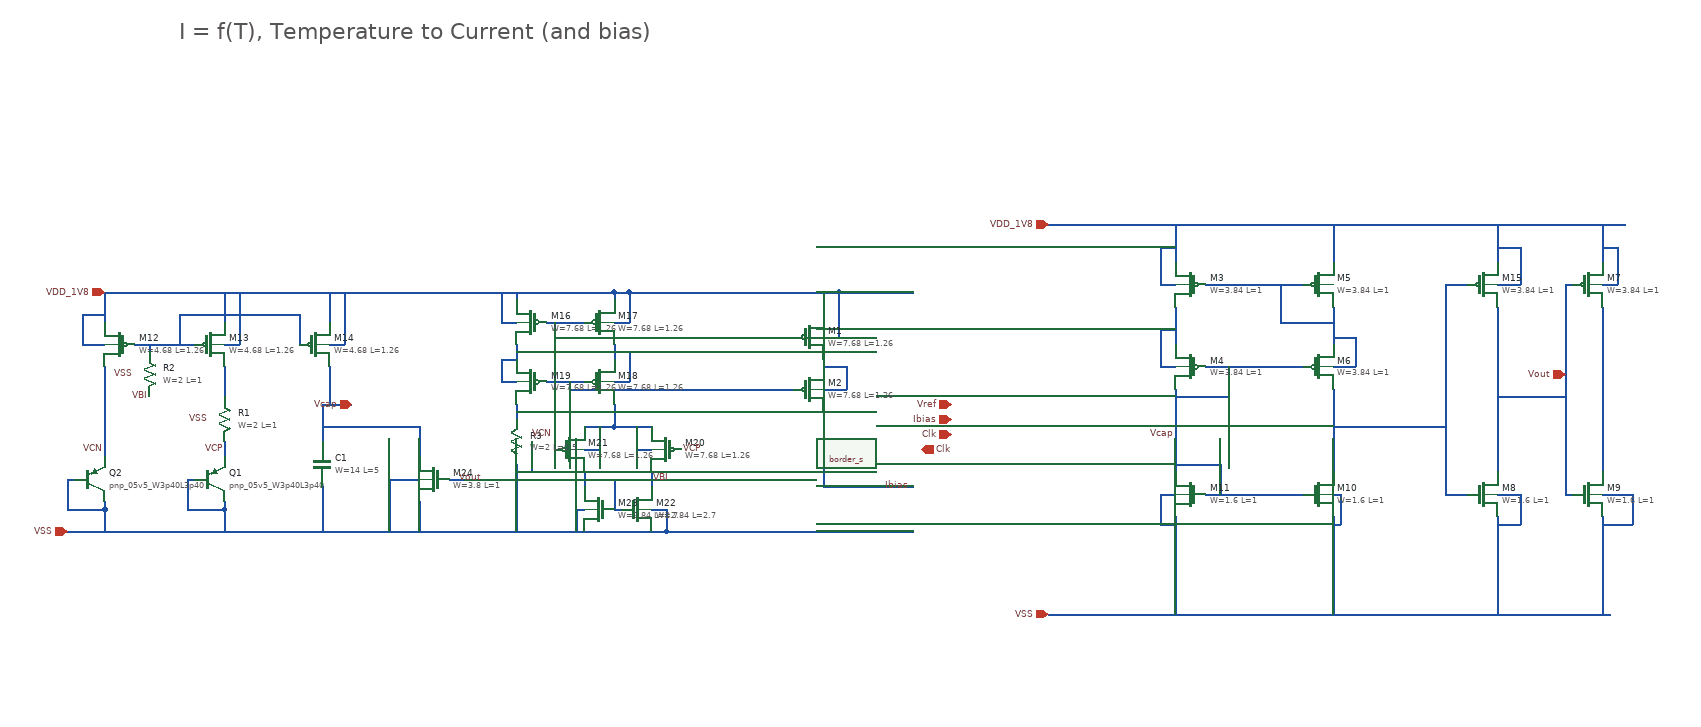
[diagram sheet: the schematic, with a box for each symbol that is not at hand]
v {xschem version=3.4.4 file_version=1.2
}
G {}
K {}
V {}
S {}
E {}
T {I = f(T), Temperature to Current (and bias)} -560 -540 0 0 1 1 {}
N -660 -180 -660 -140 {
lab=VDD_1V8}
N -500 -180 -500 -140 {
lab=VDD_1V8}
N -500 -80 -500 -40 {
lab=#net1}
N -500 20 -500 40 {
lab=VCP}
N -550 70 -540 70 {
lab=VSS}
N -550 70 -550 110 {
lab=VSS}
N -550 110 -500 110 {
lab=VSS}
N -500 100 -500 110 {
lab=VSS}
N -710 70 -700 70 {
lab=VSS}
N -710 70 -710 110 {
lab=VSS}
N -710 110 -660 110 {
lab=VSS}
N -660 100 -660 110 {
lab=VSS}
N -660 -80 -660 40 {
lab=VCN}
N -660 -180 20 -180 {
lab=VDD_1V8}
N -620 -110 -540 -110 {
lab=#net2}
N -560 -150 -560 -110 {
lab=#net2}
N -360 -180 -360 -140 {
lab=VDD_1V8}
N -560 -150 -400 -150 {
lab=#net2}
N -400 -150 -400 -110 {
lab=#net2}
N -360 -80 -360 -30 {
lab=Vcap}
N -110 -180 -110 -170 {
lab=VDD_1V8}
N 20 -180 20 -170 {
lab=VDD_1V8}
N -70 -140 -20 -140 {
lab=#net3}
N -60 -140 -60 -110 {
lab=#net3}
N -70 -60 -20 -60 {
lab=#net4}
N -60 -60 -60 -20 {
lab=#net4}
N -110 -20 -60 -20 {
lab=#net4}
N -110 -110 -110 -90 {
lab=#net3}
N -110 -100 -60 -100 {
lab=#net3}
N -60 -110 -60 -100 {
lab=#net3}
N -110 -30 -110 -10 {
lab=#net4}
N 20 -110 20 -90 {
lab=#net5}
N 20 -30 20 0 {
lab=#net6}
N -20 0 20 0 {
lab=#net6}
N 20 0 70 0 {
lab=#net6}
N -20 60 -20 80 {
lab=#net7}
N 70 60 70 80 {
lab=VBI}
N 20 110 30 110 {
lab=VBI}
N 20 70 20 110 {
lab=VBI}
N 20 70 70 70 {
lab=VBI}
N -20 140 70 140 {
lab=VSS}
N -710 140 -20 140 {
lab=VSS}
N -660 110 -660 140 {
lab=VSS}
N -500 110 -500 140 {
lab=VSS}
N -110 50 -110 140 {
lab=VSS}
N -90 20 -90 60 {
lab=VSS}
N -110 60 -90 60 {
lab=VSS}
N -60 10 -60 30 {
lab=VCN}
N 70 110 90 110 {
lab=VSS}
N 90 110 90 140 {
lab=VSS}
N 70 140 90 140 {
lab=VSS}
N -30 110 -20 110 {
lab=VSS}
N -30 110 -30 140 {
lab=VSS}
N 20 -60 40 -60 {
lab=#net5}
N 40 -100 40 -60 {
lab=#net5}
N 20 -100 40 -100 {
lab=#net5}
N 20 -140 40 -140 {
lab=VDD_1V8}
N 40 -180 40 -140 {
lab=VDD_1V8}
N 20 -180 40 -180 {
lab=VDD_1V8}
N -130 -60 -110 -60 {
lab=#net3}
N -130 -90 -130 -60 {
lab=#net3}
N -130 -90 -110 -90 {
lab=#net3}
N -130 -140 -110 -140 {
lab=VDD_1V8}
N -130 -180 -130 -140 {
lab=VDD_1V8}
N -20 30 0 30 {
lab=#net6}
N 0 0 0 30 {
lab=#net6}
N 50 30 70 30 {
lab=#net6}
N 50 0 50 30 {
lab=#net6}
N -360 -110 -340 -110 {
lab=VDD_1V8}
N -340 -180 -340 -110 {
lab=VDD_1V8}
N -500 -110 -480 -110 {
lab=VDD_1V8}
N -480 -180 -480 -110 {
lab=VDD_1V8}
N -690 -110 -660 -110 {
lab=VDD_1V8}
N -690 -150 -690 -110 {
lab=VDD_1V8}
N -690 -150 -660 -150 {
lab=VDD_1V8}
N -370 -30 -370 20 {
lab=Vcap}
N -370 80 -370 130 {
lab=VSS}
N -200 70 -180 70 {
lab=Vcap}
N -280 70 -240 70 {
lab=VSS}
N -240 0 -240 40 {
lab=Vcap}
N -370 -30 -330 -30 {
lab=Vcap}
N -280 70 -280 130 {
lab=VSS}
N -240 100 -240 130 {
lab=VSS}
N -280 130 -280 140 {
lab=VSS}
N -240 130 -240 140 {
lab=VSS}
N -370 130 -370 140 {
lab=VSS}
N -600 -110 -600 -100 {
lab=#net2}
N -370 0 -240 0 {
lab=Vcap}
N 40 -180 170 -180 {
lab=VDD_1V8}
N 90 140 220 140 {
lab=VSS}
N -60 -120 260 -120 {
lab=#net3}
N -40 -60 -40 -50 {
lab=#net4}
N -40 -50 260 -50 {
lab=#net4}
N 300 -90 300 -80 {
lab=#net8}
N 300 -50 330 -50 {
lab=#net8}
N 330 -80 330 -50 {
lab=#net8}
N 300 -80 330 -80 {
lab=#net8}
N 300 -120 320 -120 {
lab=VDD_1V8}
N 320 -180 320 -120 {
lab=VDD_1V8}
N 170 -180 320 -180 {
lab=VDD_1V8}
N 300 -180 300 -150 {
lab=VDD_1V8}
N 300 -20 300 40 {
lab=Ibias}
N 320 -180 420 -180 {
lab=VDD_1V8}
N 220 140 420 140 {
lab=VSS}
N 300 40 300 80 {
lab=Ibias}
N 300 80 420 80 {
lab=Ibias}
N 600 -270 1350 -270 {
lab=VDD_1V8}
N 600 250 1350 250 {
lab=VSS}
N 980 120 980 250 {
lab=VSS}
N 1350 -270 1370 -270 {
lab=VDD_1V8}
N 750 90 770 90 {
lab=VSS}
N 750 90 750 130 {
lab=VSS}
N 750 130 770 130 {
lab=VSS}
N 980 90 990 90 {
lab=VSS}
N 990 90 990 130 {
lab=VSS}
N 980 130 990 130 {
lab=VSS}
N 750 -190 770 -190 {
lab=VDD_1V8}
N 750 -240 750 -190 {
lab=VDD_1V8}
N 750 -240 770 -240 {
lab=VDD_1V8}
N 750 -80 770 -80 {
lab=#net9}
N 750 -130 750 -80 {
lab=#net9}
N 750 -130 770 -130 {
lab=#net9}
N 770 -270 770 -220 {
lab=VDD_1V8}
N 770 -160 770 -110 {
lab=#net9}
N 980 -160 980 -110 {
lab=#net10}
N 980 -270 980 -220 {
lab=VDD_1V8}
N 810 -190 940 -190 {
lab=#net10}
N 910 -190 910 -140 {
lab=#net10}
N 910 -140 980 -140 {
lab=#net10}
N 810 -80 940 -80 {
lab=Vcap}
N 980 -50 980 60 {
lab=#net11}
N 770 -50 770 60 {
lab=Vcap}
N 770 120 770 250 {
lab=VSS}
N 810 90 940 90 {
lab=Vcap}
N 830 50 830 90 {
lab=Vcap}
N 770 50 830 50 {
lab=Vcap}
N 840 -80 840 -40 {
lab=Vcap}
N 770 -40 840 -40 {
lab=Vcap}
N 980 -80 1010 -80 {
lab=#net10}
N 1010 -120 1010 -80 {
lab=#net10}
N 980 -120 1010 -120 {
lab=#net10}
N 1200 -270 1200 -220 {
lab=VDD_1V8}
N 1340 -270 1340 -220 {
lab=VDD_1V8}
N 1200 -160 1200 60 {
lab=Vout}
N 1340 -160 1340 60 {
lab=#net12}
N 1200 -190 1230 -190 {
lab=VDD_1V8}
N 1230 -240 1230 -190 {
lab=VDD_1V8}
N 1200 -240 1230 -240 {
lab=VDD_1V8}
N 1340 -190 1360 -190 {
lab=VDD_1V8}
N 1360 -240 1360 -190 {
lab=VDD_1V8}
N 1340 -240 1360 -240 {
lab=VDD_1V8}
N 1290 -190 1300 -190 {
lab=Vout}
N 1290 -190 1290 90 {
lab=Vout}
N 1290 90 1300 90 {
lab=Vout}
N 1340 120 1340 250 {
lab=VSS}
N 1200 120 1200 250 {
lab=VSS}
N 1200 90 1230 90 {
lab=VSS}
N 1230 90 1230 130 {
lab=VSS}
N 1200 130 1230 130 {
lab=VSS}
N 1340 90 1380 90 {
lab=VSS}
N 1380 90 1380 130 {
lab=VSS}
N 1340 130 1380 130 {
lab=VSS}
N 1200 -40 1290 -40 {
lab=Vout}
N 1130 -190 1160 -190 {
lab=#net11}
N 1130 -190 1130 90 {
lab=#net11}
N 1130 90 1160 90 {
lab=#net11}
N 980 0 1130 0 {
lab=#net11}
C {cborder/border_s.sym} 380 330 0 0 {
user="wulff"
company="wulff"}
C {devices/ipin.sym} -660 -180 0 0 {name=p1 lab=VDD_1V8}
C {devices/ipin.sym} -710 140 0 0 {name=p2 lab=VSS}
C {devices/lab_wire.sym} -660 30 0 0 {name=p3 sig_type=std_logic lab=VCN}
C {sky130_fd_pr/pnp_05v5.sym} -520 70 0 0 {name=Q1
model=pnp_05v5_W3p40L3p40
m=8
spiceprefix=X
}
C {sky130_fd_pr/res_high_po.sym} -500 -10 0 0 {name=R1
W=2
L=1
model=res_high_po
mult=0.25}
C {sky130_fd_pr/pnp_05v5.sym} -680 70 0 0 {name=Q2
model=pnp_05v5_W3p40L3p40
m=8
spiceprefix=X
}
C {sky130_fd_pr/pfet_01v8.sym} -640 -110 0 1 {name=M12
L=1.26
W=4.68
nf=1
mult=1
ad="'int((nf+1)/2) * W/nf * 0.29'"
pd="'2*int((nf+1)/2) * (W/nf + 0.29)'"
as="'int((nf+2)/2) * W/nf * 0.29'"
ps="'2*int((nf+2)/2) * (W/nf + 0.29)'"
nrd="'0.29 / W'" nrs="'0.29 / W'"
sa=0 sb=0 sd=0
model=pfet_01v8
spiceprefix=X
}
C {sky130_fd_pr/pfet_01v8.sym} -520 -110 0 0 {name=M13
L=1.26
W=4.68
nf=1
mult=1
ad="'int((nf+1)/2) * W/nf * 0.29'"
pd="'2*int((nf+1)/2) * (W/nf + 0.29)'"
as="'int((nf+2)/2) * W/nf * 0.29'"
ps="'2*int((nf+2)/2) * (W/nf + 0.29)'"
nrd="'0.29 / W'" nrs="'0.29 / W'"
sa=0 sb=0 sd=0
model=pfet_01v8
spiceprefix=X
}
C {sky130_fd_pr/pfet_01v8.sym} -380 -110 0 0 {name=M14
L=1.26
W=4.68
nf=1
mult=1
ad="'int((nf+1)/2) * W/nf * 0.29'"
pd="'2*int((nf+1)/2) * (W/nf + 0.29)'"
as="'int((nf+2)/2) * W/nf * 0.29'"
ps="'2*int((nf+2)/2) * (W/nf + 0.29)'"
nrd="'0.29 / W'" nrs="'0.29 / W'"
sa=0 sb=0 sd=0
model=pfet_01v8
spiceprefix=X
}
C {sky130_fd_pr/pfet_01v8.sym} -90 -140 0 1 {name=M16
L=1.26
W=7.68
nf=1
mult=1
ad="'int((nf+1)/2) * W/nf * 0.29'"
pd="'2*int((nf+1)/2) * (W/nf + 0.29)'"
as="'int((nf+2)/2) * W/nf * 0.29'"
ps="'2*int((nf+2)/2) * (W/nf + 0.29)'"
nrd="'0.29 / W'" nrs="'0.29 / W'"
sa=0 sb=0 sd=0
model=pfet_01v8
spiceprefix=X
}
C {sky130_fd_pr/pfet_01v8.sym} 0 -140 0 0 {name=M17
L=1.26
W=7.68
nf=1
mult=1
ad="'int((nf+1)/2) * W/nf * 0.29'"
pd="'2*int((nf+1)/2) * (W/nf + 0.29)'"
as="'int((nf+2)/2) * W/nf * 0.29'"
ps="'2*int((nf+2)/2) * (W/nf + 0.29)'"
nrd="'0.29 / W'" nrs="'0.29 / W'"
sa=0 sb=0 sd=0
model=pfet_01v8
spiceprefix=X
}
C {sky130_fd_pr/pfet_01v8.sym} 0 -60 0 0 {name=M18
L=1.26
W=7.68
nf=1
mult=1
ad="'int((nf+1)/2) * W/nf * 0.29'"
pd="'2*int((nf+1)/2) * (W/nf + 0.29)'"
as="'int((nf+2)/2) * W/nf * 0.29'"
ps="'2*int((nf+2)/2) * (W/nf + 0.29)'"
nrd="'0.29 / W'" nrs="'0.29 / W'"
sa=0 sb=0 sd=0
model=pfet_01v8
spiceprefix=X
}
C {sky130_fd_pr/pfet_01v8.sym} -90 -60 0 1 {name=M19
L=1.26
W=7.68
nf=1
mult=1
ad="'int((nf+1)/2) * W/nf * 0.29'"
pd="'2*int((nf+1)/2) * (W/nf + 0.29)'"
as="'int((nf+2)/2) * W/nf * 0.29'"
ps="'2*int((nf+2)/2) * (W/nf + 0.29)'"
nrd="'0.29 / W'" nrs="'0.29 / W'"
sa=0 sb=0 sd=0
model=pfet_01v8
spiceprefix=X
}
C {sky130_fd_pr/pfet_01v8.sym} 90 30 0 1 {name=M20
L=1.26
W=7.68
nf=1
mult=1
ad="'int((nf+1)/2) * W/nf * 0.29'"
pd="'2*int((nf+1)/2) * (W/nf + 0.29)'"
as="'int((nf+2)/2) * W/nf * 0.29'"
ps="'2*int((nf+2)/2) * (W/nf + 0.29)'"
nrd="'0.29 / W'" nrs="'0.29 / W'"
sa=0 sb=0 sd=0
model=pfet_01v8
spiceprefix=X
}
C {sky130_fd_pr/pfet_01v8.sym} -40 30 0 0 {name=M21
L=1.26
W=7.68
nf=1
mult=1
ad="'int((nf+1)/2) * W/nf * 0.29'"
pd="'2*int((nf+1)/2) * (W/nf + 0.29)'"
as="'int((nf+2)/2) * W/nf * 0.29'"
ps="'2*int((nf+2)/2) * (W/nf + 0.29)'"
nrd="'0.29 / W'" nrs="'0.29 / W'"
sa=0 sb=0 sd=0
model=pfet_01v8
spiceprefix=X
}
C {sky130_fd_pr/nfet_01v8.sym} 50 110 0 0 {name=M22
L=2.7
W=2.84
nf=1
mult=1
ad="'int((nf+1)/2) * W/nf * 0.29'"
pd="'2*int((nf+1)/2) * (W/nf + 0.29)'"
as="'int((nf+2)/2) * W/nf * 0.29'"
ps="'2*int((nf+2)/2) * (W/nf + 0.29)'"
nrd="'0.29 / W'" nrs="'0.29 / W'"
sa=0 sb=0 sd=0
model=nfet_01v8
spiceprefix=X
}
C {sky130_fd_pr/nfet_01v8.sym} 0 110 0 1 {name=M23
L=2.7
W=2.84
nf=1
mult=1
ad="'int((nf+1)/2) * W/nf * 0.29'"
pd="'2*int((nf+1)/2) * (W/nf + 0.29)'"
as="'int((nf+2)/2) * W/nf * 0.29'"
ps="'2*int((nf+2)/2) * (W/nf + 0.29)'"
nrd="'0.29 / W'" nrs="'0.29 / W'"
sa=0 sb=0 sd=0
model=nfet_01v8
spiceprefix=X
}
C {sky130_fd_pr/res_high_po.sym} -110 20 0 1 {name=R3
W=2
L=0.5
model=res_high_po
mult=0.05}
C {devices/lab_wire.sym} -500 30 0 0 {name=p9 sig_type=std_logic lab=VCP}
C {devices/lab_wire.sym} -60 10 0 0 {name=p10 sig_type=std_logic lab=VCN}
C {devices/lab_wire.sym} 110 30 0 1 {name=p12 sig_type=std_logic lab=VCP}
C {devices/lab_wire.sym} -520 -10 0 0 {name=p8 sig_type=std_logic lab=VSS}
C {sky130_fd_pr/cap_mim_m3_1.sym} -370 50 0 1 {name=C1 model=cap_mim_m3_1 W=14 L=5 MF=25 spiceprefix=X}
C {sky130_fd_pr/nfet_01v8.sym} -220 70 0 1 {name=M24
L=1
W=3.8
nf=1
mult=1
ad="'int((nf+1)/2) * W/nf * 0.29'"
pd="'2*int((nf+1)/2) * (W/nf + 0.29)'"
as="'int((nf+2)/2) * W/nf * 0.29'"
ps="'2*int((nf+2)/2) * (W/nf + 0.29)'"
nrd="'0.29 / W'" nrs="'0.29 / W'"
sa=0 sb=0 sd=0
model=nfet_01v8
spiceprefix=X
}
C {devices/ipin.sym} 430 30 0 1 {name=p6 lab=Clk
}
C {devices/opin.sym} -330 -30 2 1 {name=p13 lab=Vcap
}
C {sky130_fd_pr/res_high_po.sym} -600 -70 0 0 {name=R2
W=2
L=1
model=res_high_po
mult=0.25}
C {devices/lab_wire.sym} -600 -40 0 0 {name=p4 sig_type=std_logic lab=VBI}
C {devices/lab_wire.sym} -620 -70 0 0 {name=p5 sig_type=std_logic lab=VSS}
C {devices/lab_wire.sym} 70 70 0 1 {name=p7 sig_type=std_logic lab=VBI}
C {sky130_fd_pr/pfet_01v8.sym} 280 -120 0 0 {name=M1
L=1.26
W=7.68
nf=1
mult=1
ad="'int((nf+1)/2) * W/nf * 0.29'"
pd="'2*int((nf+1)/2) * (W/nf + 0.29)'"
as="'int((nf+2)/2) * W/nf * 0.29'"
ps="'2*int((nf+2)/2) * (W/nf + 0.29)'"
nrd="'0.29 / W'" nrs="'0.29 / W'"
sa=0 sb=0 sd=0
model=pfet_01v8
spiceprefix=X
}
C {sky130_fd_pr/pfet_01v8.sym} 280 -50 0 0 {name=M2
L=1.26
W=7.68
nf=1
mult=1
ad="'int((nf+1)/2) * W/nf * 0.29'"
pd="'2*int((nf+1)/2) * (W/nf + 0.29)'"
as="'int((nf+2)/2) * W/nf * 0.29'"
ps="'2*int((nf+2)/2) * (W/nf + 0.29)'"
nrd="'0.29 / W'" nrs="'0.29 / W'"
sa=0 sb=0 sd=0
model=pfet_01v8
spiceprefix=X
}
C {devices/ipin.sym} 600 -270 0 0 {name=p11 lab=VDD_1V8}
C {devices/ipin.sym} 600 250 0 0 {name=p14 lab=VSS}
C {devices/ipin.sym} 470 -30 0 0 {name=p16 lab=Vref}
C {devices/ipin.sym} 470 -10 0 0 {name=p24 lab=Ibias}
C {sky130_fd_pr/pfet_01v8.sym} 790 -190 0 1 {name=M3
L=1
W=3.84
nf=1
mult=1
ad="'int((nf+1)/2) * W/nf * 0.29'"
pd="'2*int((nf+1)/2) * (W/nf + 0.29)'"
as="'int((nf+2)/2) * W/nf * 0.29'"
ps="'2*int((nf+2)/2) * (W/nf + 0.29)'"
nrd="'0.29 / W'" nrs="'0.29 / W'"
sa=0 sb=0 sd=0
model=pfet_01v8
spiceprefix=X
}
C {sky130_fd_pr/nfet_01v8.sym} 960 90 0 0 {name=M10
L=1
W=1.6
nf=1
mult=1
ad="'int((nf+1)/2) * W/nf * 0.29'"
pd="'2*int((nf+1)/2) * (W/nf + 0.29)'"
as="'int((nf+2)/2) * W/nf * 0.29'"
ps="'2*int((nf+2)/2) * (W/nf + 0.29)'"
nrd="'0.29 / W'" nrs="'0.29 / W'"
sa=0 sb=0 sd=0
model=nfet_01v8
spiceprefix=X
}
C {sky130_fd_pr/nfet_01v8.sym} 790 90 0 1 {name=M11
L=1
W=1.6
nf=1
mult=1
ad="'int((nf+1)/2) * W/nf * 0.29'"
pd="'2*int((nf+1)/2) * (W/nf + 0.29)'"
as="'int((nf+2)/2) * W/nf * 0.29'"
ps="'2*int((nf+2)/2) * (W/nf + 0.29)'"
nrd="'0.29 / W'" nrs="'0.29 / W'"
sa=0 sb=0 sd=0
model=nfet_01v8
spiceprefix=X
}
C {devices/ipin.sym} 470 10 0 0 {name=p18 lab=Clk}
C {devices/lab_wire.sym} 380 80 0 1 {name=p17 sig_type=std_logic lab=Ibias}
C {sky130_fd_pr/pfet_01v8.sym} 960 -190 0 0 {name=M5
L=1
W=3.84
nf=1
mult=1
ad="'int((nf+1)/2) * W/nf * 0.29'"
pd="'2*int((nf+1)/2) * (W/nf + 0.29)'"
as="'int((nf+2)/2) * W/nf * 0.29'"
ps="'2*int((nf+2)/2) * (W/nf + 0.29)'"
nrd="'0.29 / W'" nrs="'0.29 / W'"
sa=0 sb=0 sd=0
model=pfet_01v8
spiceprefix=X
}
C {sky130_fd_pr/pfet_01v8.sym} 1180 -190 0 0 {name=M15
L=1
W=3.84
nf=1
mult=1
ad="'int((nf+1)/2) * W/nf * 0.29'"
pd="'2*int((nf+1)/2) * (W/nf + 0.29)'"
as="'int((nf+2)/2) * W/nf * 0.29'"
ps="'2*int((nf+2)/2) * (W/nf + 0.29)'"
nrd="'0.29 / W'" nrs="'0.29 / W'"
sa=0 sb=0 sd=0
model=pfet_01v8
spiceprefix=X
}
C {devices/opin.sym} 1290 -70 2 1 {name=p15 lab=Vout
}
C {sky130_fd_pr/pfet_01v8.sym} 790 -80 0 1 {name=M4
L=1
W=3.84
nf=1
mult=1
ad="'int((nf+1)/2) * W/nf * 0.29'"
pd="'2*int((nf+1)/2) * (W/nf + 0.29)'"
as="'int((nf+2)/2) * W/nf * 0.29'"
ps="'2*int((nf+2)/2) * (W/nf + 0.29)'"
nrd="'0.29 / W'" nrs="'0.29 / W'"
sa=0 sb=0 sd=0
model=pfet_01v8
spiceprefix=X
}
C {sky130_fd_pr/pfet_01v8.sym} 960 -80 0 0 {name=M6
L=1
W=3.84
nf=1
mult=1
ad="'int((nf+1)/2) * W/nf * 0.29'"
pd="'2*int((nf+1)/2) * (W/nf + 0.29)'"
as="'int((nf+2)/2) * W/nf * 0.29'"
ps="'2*int((nf+2)/2) * (W/nf + 0.29)'"
nrd="'0.29 / W'" nrs="'0.29 / W'"
sa=0 sb=0 sd=0
model=pfet_01v8
spiceprefix=X
}
C {sky130_fd_pr/pfet_01v8.sym} 1320 -190 0 0 {name=M7
L=1
W=3.84
nf=1
mult=1
ad="'int((nf+1)/2) * W/nf * 0.29'"
pd="'2*int((nf+1)/2) * (W/nf + 0.29)'"
as="'int((nf+2)/2) * W/nf * 0.29'"
ps="'2*int((nf+2)/2) * (W/nf + 0.29)'"
nrd="'0.29 / W'" nrs="'0.29 / W'"
sa=0 sb=0 sd=0
model=pfet_01v8
spiceprefix=X
}
C {sky130_fd_pr/nfet_01v8.sym} 1180 90 0 0 {name=M8
L=1
W=1.6
nf=1
mult=1
ad="'int((nf+1)/2) * W/nf * 0.29'"
pd="'2*int((nf+1)/2) * (W/nf + 0.29)'"
as="'int((nf+2)/2) * W/nf * 0.29'"
ps="'2*int((nf+2)/2) * (W/nf + 0.29)'"
nrd="'0.29 / W'" nrs="'0.29 / W'"
sa=0 sb=0 sd=0
model=nfet_01v8
spiceprefix=X
}
C {sky130_fd_pr/nfet_01v8.sym} 1320 90 0 0 {name=M9
L=1
W=1.6
nf=1
mult=1
ad="'int((nf+1)/2) * W/nf * 0.29'"
pd="'2*int((nf+1)/2) * (W/nf + 0.29)'"
as="'int((nf+2)/2) * W/nf * 0.29'"
ps="'2*int((nf+2)/2) * (W/nf + 0.29)'"
nrd="'0.29 / W'" nrs="'0.29 / W'"
sa=0 sb=0 sd=0
model=nfet_01v8
spiceprefix=X
}
C {devices/lab_wire.sym} 770 10 0 0 {name=p19 sig_type=std_logic lab=Vcap}
C {devices/lab_wire.sym} -190 70 0 1 {name=p20 sig_type=std_logic lab=Vout}
